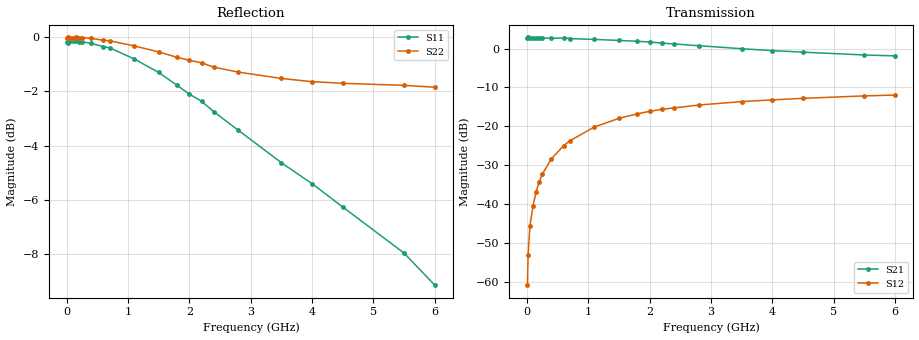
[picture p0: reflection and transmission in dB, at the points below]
! SIEMENS Discrete & RF Semiconductors
! BFY180
! Si NPN RF Bipolar Junction Transistor in MICRO-X
! VCE = 4 V  IC = 0.4 mA
! Common Emitter S-Parameters:  May  1997
# GHz  S  MA  R  50
!  f  S11  S21  S12  S22
! GHz  MAG  ANG  MAG  ANG  MAG  ANG  MAG  ANG
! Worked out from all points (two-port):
!   36 points, 10 MHz to 6 GHz, reference 50 ohm
!   highest |S21| = 2.89 dB at 20 MHz (marker M1); lowest = -1.9 dB at 6 GHz (marker M2)
!   |S21| within 3 dB of the highest: start of sweep to 3.578 GHz
!   lowest |S11| = -9.2 dB at 6 GHz (marker M3), VSWR 2.07, Z = 28.1 - j17.2 ohm
!   |S11| at or under -10 dB: nowhere
!   |S22| runs from -1.8 to 0.0 dB; largest |S21 - S12| = 1.4
!   S11 on the Smith chart (normalised r, x): 10 MHz: open; 700 MHz: 0.65, -5.29; 1.5 GHz: 0.53, -2.41; 2.4 GHz: 0.50, -1.42; 4 GHz: 0.51, -0.77; 6 GHz: 0.56, -0.34
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0.01  0.982 -0.1  1.373 179.9  0.0009 99.0  0.9975 -0.2
0.02  0.9765 -0.6  1.395 179.1  0.0022 96.8  0.9999 -0.5
0.05  0.9848 -1.5  1.365 178.2  0.0052 82.7  0.9989 -1.0
0.1  0.9853 -3.0  1.384 176.2  0.0094 88.1  0.9976 -2.2
0.15  0.9853 -4.6  1.37 174.5  0.0143 87.6  0.9997 -3.3
0.2  0.9823 -6.0  1.361 172.2  0.019 84.4  0.9978 -4.4
0.25  0.9813 -7.7  1.372 170.5  0.024 84.8  0.999 -5.5
0.4  0.9746 -11.9  1.358 164.3  0.0381 81.5  0.9956 -8.6
0.6  0.9612 -18.0  1.37 155.9  0.0564 75.6  0.9879 -13.0
0.7  0.9565 -21.1  1.346 153.0  0.0649 72.9  0.9856 -15.1
1.1  0.9125 -32.2  1.313 138.0  0.0978 63.7  0.9644 -23.4
1.5  0.8612 -43.4  1.275 124.0  0.1264 55.0  0.94 -31.3
1.8  0.8155 -51.7  1.244 113.3  0.1445 49.6  0.9185 -36.7
2  0.7856 -56.5  1.216 106.3  0.1556 45.8  0.9074 -40.2
2.2  0.7618 -61.1  1.18 100.1  0.1652 42.0  0.8971 -43.7
2.4  0.7286 -65.9  1.146 93.9  0.1724 38.8  0.8807 -46.9
2.8  0.6733 -74.0  1.091 82.8  0.1876 33.0  0.8626 -52.8
3.5  0.5867 -86.4  0.996 64.6  0.2078 24.2  0.8396 -62.5
4  0.5366 -95.2  0.943 53.2  0.2188 18.5  0.8282 -69.3
4.5  0.486 -103.0  0.9 42.6  0.2289 13.4  0.8225 -76.1
5.5  0.3994 -120.0  0.828 23.3  0.246 3.6  0.8152 -90.1
6  0.3485 -129.5  0.806 14.7  0.2524 -1.4  0.8089 -97.1
